VERSION 5.7 ;
  NOWIREEXTENSIONATPIN ON ;
  DIVIDERCHAR "/" ;
  BUSBITCHARS "[]" ;
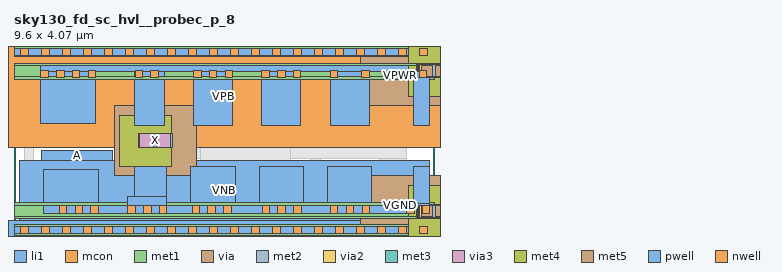
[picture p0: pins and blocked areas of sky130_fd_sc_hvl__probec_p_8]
MACRO sky130_fd_sc_hvl__probec_p_8
  CLASS BLOCK ;
  FOREIGN sky130_fd_sc_hvl__probec_p_8 ;
  ORIGIN 0.000 0.000 ;
  SIZE 9.600 BY 4.070 ;
  PIN A
    ANTENNAGATEAREA 3.375000 ;
    PORT
      LAYER li1 ;
        RECT 0.635 1.580 2.245 1.815 ;
    END
  END A
  PIN VGND
    USE GROUND ;
    PORT
      LAYER li1 ;
        RECT 0.675 0.550 1.925 1.385 ;
        RECT 2.765 0.760 3.495 1.445 ;
        RECT 2.605 0.550 3.495 0.760 ;
        RECT 4.045 0.550 5.055 1.445 ;
        RECT 5.605 0.550 6.615 1.445 ;
        RECT 7.165 0.550 8.175 1.445 ;
        RECT 9.135 0.600 9.505 1.445 ;
        RECT 8.975 0.550 9.505 0.600 ;
        RECT 0.675 0.380 9.505 0.550 ;
      LAYER mcon ;
        RECT 1.035 0.380 1.205 0.550 ;
        RECT 1.395 0.380 1.565 0.550 ;
        RECT 1.755 0.380 1.925 0.550 ;
        RECT 2.605 0.380 2.775 0.550 ;
        RECT 2.965 0.380 3.135 0.550 ;
        RECT 3.325 0.380 3.495 0.550 ;
        RECT 4.070 0.380 4.240 0.550 ;
        RECT 4.430 0.380 4.600 0.550 ;
        RECT 4.790 0.380 4.960 0.550 ;
        RECT 5.670 0.380 5.840 0.550 ;
        RECT 6.030 0.380 6.200 0.550 ;
        RECT 6.390 0.380 6.560 0.550 ;
        RECT 7.235 0.380 7.405 0.550 ;
        RECT 7.595 0.380 7.765 0.550 ;
        RECT 7.955 0.380 8.125 0.550 ;
        RECT 8.975 0.380 9.145 0.550 ;
        RECT 9.335 0.380 9.505 0.550 ;
      LAYER met1 ;
        RECT 0.000 0.565 9.600 0.625 ;
        RECT 0.000 0.305 9.920 0.565 ;
        RECT 0.000 0.255 9.600 0.305 ;
      LAYER via ;
        RECT 9.310 0.305 9.570 0.565 ;
        RECT 9.630 0.305 9.890 0.565 ;
      LAYER met2 ;
        RECT 9.215 0.285 9.985 0.565 ;
      LAYER via2 ;
        RECT 9.260 0.285 9.540 0.565 ;
        RECT 9.660 0.285 9.940 0.565 ;
      LAYER met3 ;
        RECT 9.210 0.260 9.990 0.590 ;
      LAYER via3 ;
        RECT 9.240 0.265 9.560 0.585 ;
        RECT 9.640 0.265 9.960 0.585 ;
      LAYER met4 ;
        RECT 9.010 -0.155 10.190 1.025 ;
      LAYER met5 ;
        RECT 7.910 -0.365 10.410 1.235 ;
    END
  END VGND
  PIN VNB
    ANTENNADIFFAREA 1.632000 ;
    PORT
      LAYER pwell ;
        RECT 0.115 0.215 9.505 1.585 ;
        RECT -0.130 -0.215 9.730 0.215 ;
      LAYER li1 ;
        RECT 0.000 -0.085 9.600 0.085 ;
      LAYER mcon ;
        RECT 0.155 -0.085 0.325 0.085 ;
        RECT 0.635 -0.085 0.805 0.085 ;
        RECT 1.115 -0.085 1.285 0.085 ;
        RECT 1.595 -0.085 1.765 0.085 ;
        RECT 2.075 -0.085 2.245 0.085 ;
        RECT 2.555 -0.085 2.725 0.085 ;
        RECT 3.035 -0.085 3.205 0.085 ;
        RECT 3.515 -0.085 3.685 0.085 ;
        RECT 3.995 -0.085 4.165 0.085 ;
        RECT 4.475 -0.085 4.645 0.085 ;
        RECT 4.955 -0.085 5.125 0.085 ;
        RECT 5.435 -0.085 5.605 0.085 ;
        RECT 5.915 -0.085 6.085 0.085 ;
        RECT 6.395 -0.085 6.565 0.085 ;
        RECT 6.875 -0.085 7.045 0.085 ;
        RECT 7.355 -0.085 7.525 0.085 ;
        RECT 7.835 -0.085 8.005 0.085 ;
        RECT 8.315 -0.085 8.485 0.085 ;
        RECT 8.795 -0.085 8.965 0.085 ;
        RECT 9.275 -0.085 9.445 0.085 ;
      LAYER met1 ;
        RECT 0.000 -0.115 9.600 0.115 ;
    END
  END VNB
  PIN VPB
    ANTENNADIFFAREA 1.632000 ;
    PORT
      LAYER nwell ;
        RECT -0.330 1.885 9.930 4.485 ;
      LAYER li1 ;
        RECT 0.000 3.985 9.600 4.155 ;
      LAYER mcon ;
        RECT 0.155 3.985 0.325 4.155 ;
        RECT 0.635 3.985 0.805 4.155 ;
        RECT 1.115 3.985 1.285 4.155 ;
        RECT 1.595 3.985 1.765 4.155 ;
        RECT 2.075 3.985 2.245 4.155 ;
        RECT 2.555 3.985 2.725 4.155 ;
        RECT 3.035 3.985 3.205 4.155 ;
        RECT 3.515 3.985 3.685 4.155 ;
        RECT 3.995 3.985 4.165 4.155 ;
        RECT 4.475 3.985 4.645 4.155 ;
        RECT 4.955 3.985 5.125 4.155 ;
        RECT 5.435 3.985 5.605 4.155 ;
        RECT 5.915 3.985 6.085 4.155 ;
        RECT 6.395 3.985 6.565 4.155 ;
        RECT 6.875 3.985 7.045 4.155 ;
        RECT 7.355 3.985 7.525 4.155 ;
        RECT 7.835 3.985 8.005 4.155 ;
        RECT 8.315 3.985 8.485 4.155 ;
        RECT 8.795 3.985 8.965 4.155 ;
        RECT 9.275 3.985 9.445 4.155 ;
      LAYER met1 ;
        RECT 0.000 3.955 9.600 4.185 ;
    END
  END VPB
  PIN VPWR
    USE POWER ;
    PORT
      LAYER li1 ;
        RECT 0.615 3.625 9.505 3.795 ;
        RECT 0.615 2.445 1.865 3.625 ;
        RECT 2.765 2.385 3.435 3.625 ;
        RECT 4.105 2.385 4.995 3.625 ;
        RECT 5.665 2.385 6.555 3.625 ;
        RECT 7.225 2.385 8.115 3.625 ;
        RECT 8.905 3.475 9.505 3.625 ;
        RECT 9.135 2.385 9.505 3.475 ;
      LAYER mcon ;
        RECT 0.615 3.475 0.785 3.645 ;
        RECT 0.975 3.475 1.145 3.645 ;
        RECT 1.335 3.475 1.505 3.645 ;
        RECT 1.695 3.475 1.865 3.645 ;
        RECT 2.770 3.475 2.940 3.645 ;
        RECT 3.130 3.475 3.300 3.645 ;
        RECT 4.105 3.475 4.275 3.645 ;
        RECT 4.465 3.475 4.635 3.645 ;
        RECT 4.825 3.475 4.995 3.645 ;
        RECT 5.665 3.475 5.835 3.645 ;
        RECT 6.025 3.475 6.195 3.645 ;
        RECT 6.385 3.475 6.555 3.645 ;
        RECT 7.230 3.475 7.400 3.645 ;
        RECT 7.945 3.475 8.115 3.645 ;
        RECT 9.265 3.475 9.435 3.645 ;
      LAYER met1 ;
        RECT 0.000 3.765 9.600 3.815 ;
        RECT 0.000 3.505 9.920 3.765 ;
        RECT 0.000 3.445 9.600 3.505 ;
      LAYER via ;
        RECT 9.310 3.505 9.570 3.765 ;
        RECT 9.630 3.505 9.890 3.765 ;
      LAYER met2 ;
        RECT 9.215 3.505 9.985 3.785 ;
      LAYER via2 ;
        RECT 9.260 3.505 9.540 3.785 ;
        RECT 9.660 3.505 9.940 3.785 ;
      LAYER met3 ;
        RECT 9.210 3.480 9.990 3.810 ;
      LAYER via3 ;
        RECT 9.240 3.485 9.560 3.805 ;
        RECT 9.640 3.485 9.960 3.805 ;
      LAYER met4 ;
        RECT 9.010 3.045 10.190 4.225 ;
      LAYER met5 ;
        RECT 7.910 2.835 10.410 4.435 ;
    END
  END VPWR
  PIN X
    PORT
      LAYER met3 ;
        RECT 2.835 1.875 3.615 2.195 ;
      LAYER via3 ;
        RECT 2.865 1.875 3.185 2.195 ;
        RECT 3.265 1.875 3.585 2.195 ;
      LAYER met4 ;
        RECT 2.410 1.445 3.590 2.625 ;
      LAYER met5 ;
        RECT 2.290 1.235 4.160 2.835 ;
    END
  END X
  OBS
      LAYER li1 ;
        RECT 0.245 2.265 0.435 3.545 ;
        RECT 2.045 2.265 2.595 3.445 ;
        RECT 0.245 2.095 2.595 2.265 ;
        RECT 0.245 1.475 0.435 2.095 ;
        RECT 2.425 1.955 2.595 2.095 ;
        RECT 3.605 2.205 3.935 3.445 ;
        RECT 5.165 2.205 5.495 3.445 ;
        RECT 6.725 2.205 7.055 3.445 ;
        RECT 8.285 3.230 8.735 3.445 ;
        RECT 8.285 2.205 8.965 3.230 ;
        RECT 3.605 1.955 8.965 2.205 ;
        RECT 2.425 1.625 3.380 1.955 ;
        RECT 3.665 1.625 8.965 1.955 ;
        RECT 0.245 0.805 0.455 1.475 ;
        RECT 2.425 1.400 2.595 1.625 ;
        RECT 2.105 1.230 2.595 1.400 ;
        RECT 2.105 0.730 2.315 1.230 ;
        RECT 3.665 0.805 3.875 1.625 ;
        RECT 5.225 0.805 5.435 1.625 ;
        RECT 6.785 0.805 6.995 1.625 ;
        RECT 8.345 0.805 8.965 1.625 ;
      LAYER mcon ;
        RECT 5.620 1.950 5.790 2.120 ;
        RECT 5.980 1.950 6.150 2.120 ;
      LAYER met1 ;
        RECT 5.560 1.905 6.210 2.165 ;
      LAYER via ;
        RECT 5.600 1.905 5.860 2.165 ;
        RECT 5.920 1.905 6.180 2.165 ;
      LAYER met2 ;
        RECT 5.440 1.895 6.210 2.175 ;
      LAYER via2 ;
        RECT 5.485 1.895 5.765 2.175 ;
        RECT 5.885 1.895 6.165 2.175 ;
      LAYER met3 ;
        RECT 5.435 1.870 6.215 2.200 ;
      LAYER via3 ;
        RECT 5.465 1.875 5.785 2.195 ;
        RECT 5.865 1.875 6.185 2.195 ;
      LAYER met4 ;
        RECT 5.010 1.445 6.190 2.625 ;
      LAYER met5 ;
        RECT 4.710 2.835 6.310 4.435 ;
        RECT 4.260 1.235 6.310 2.835 ;
        RECT 4.710 -0.365 6.310 1.235 ;
  END
END sky130_fd_sc_hvl__probec_p_8
END LIBRARY

